VERSION 5.7 ;
  NOWIREEXTENSIONATPIN ON ;
  DIVIDERCHAR "/" ;
  BUSBITCHARS "[]" ;
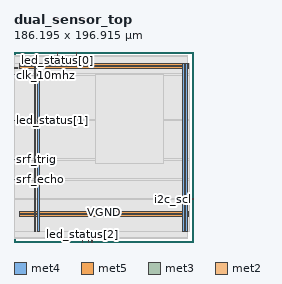
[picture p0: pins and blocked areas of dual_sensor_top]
MACRO dual_sensor_top
  CLASS BLOCK ;
  FOREIGN dual_sensor_top ;
  ORIGIN 0.000 0.000 ;
  SIZE 186.195 BY 196.915 ;
  PIN VGND
    DIRECTION INOUT ;
    USE GROUND ;
    PORT
      LAYER met4 ;
        RECT 24.340 10.640 25.940 185.200 ;
    END
    PORT
      LAYER met4 ;
        RECT 177.940 10.640 179.540 185.200 ;
    END
    PORT
      LAYER met5 ;
        RECT 5.280 30.030 180.560 31.630 ;
    END
    PORT
      LAYER met5 ;
        RECT 5.280 183.210 180.560 184.810 ;
    END
  END VGND
  PIN VPWR
    DIRECTION INOUT ;
    USE POWER ;
    PORT
      LAYER met4 ;
        RECT 21.040 10.640 22.640 185.200 ;
    END
    PORT
      LAYER met4 ;
        RECT 174.640 10.640 176.240 185.200 ;
    END
    PORT
      LAYER met5 ;
        RECT 5.280 26.730 180.560 28.330 ;
    END
    PORT
      LAYER met5 ;
        RECT 5.280 179.910 180.560 181.510 ;
    END
  END VPWR
  PIN clk_10mhz
    DIRECTION INPUT ;
    USE SIGNAL ;
    ANTENNAGATEAREA 0.852000 ;
    PORT
      LAYER met3 ;
        RECT 0.000 180.240 4.000 180.840 ;
    END
  END clk_10mhz
  PIN i2c_scl
    DIRECTION INOUT ;
    USE SIGNAL ;
    ANTENNADIFFAREA 1.782000 ;
    PORT
      LAYER met3 ;
        RECT 182.195 44.240 186.195 44.840 ;
    END
  END i2c_scl
  PIN i2c_sda
    DIRECTION INOUT ;
    USE SIGNAL ;
    ANTENNADIFFAREA 1.782000 ;
    PORT
      LAYER met2 ;
        RECT 80.590 0.000 80.870 4.000 ;
    END
  END i2c_sda
  PIN led_status[0]
    DIRECTION OUTPUT ;
    USE SIGNAL ;
    ANTENNADIFFAREA 0.445500 ;
    PORT
      LAYER met2 ;
        RECT 45.170 192.915 45.450 196.915 ;
    END
  END led_status[0]
  PIN led_status[1]
    DIRECTION OUTPUT ;
    USE SIGNAL ;
    ANTENNADIFFAREA 0.445500 ;
    PORT
      LAYER met3 ;
        RECT 0.000 125.840 4.000 126.440 ;
    END
  END led_status[1]
  PIN led_status[2]
    DIRECTION OUTPUT ;
    USE SIGNAL ;
    ANTENNADIFFAREA 0.445500 ;
    PORT
      LAYER met2 ;
        RECT 70.930 0.000 71.210 4.000 ;
    END
  END led_status[2]
  PIN pwr_ctrl
    DIRECTION OUTPUT ;
    USE SIGNAL ;
    ANTENNADIFFAREA 0.445500 ;
    PORT
      LAYER met2 ;
        RECT 77.370 0.000 77.650 4.000 ;
    END
  END pwr_ctrl
  PIN rst_n
    DIRECTION INPUT ;
    USE SIGNAL ;
    ANTENNAGATEAREA 0.196500 ;
    PORT
      LAYER met3 ;
        RECT 0.000 173.440 4.000 174.040 ;
    END
  END rst_n
  PIN srf_echo
    DIRECTION INPUT ;
    USE SIGNAL ;
    ANTENNAGATEAREA 0.196500 ;
    PORT
      LAYER met3 ;
        RECT 0.000 64.640 4.000 65.240 ;
    END
  END srf_echo
  PIN srf_trig
    DIRECTION OUTPUT ;
    USE SIGNAL ;
    ANTENNADIFFAREA 0.445500 ;
    PORT
      LAYER met3 ;
        RECT 0.000 85.040 4.000 85.640 ;
    END
  END srf_trig
  PIN uart_tx_pin
    DIRECTION OUTPUT ;
    USE SIGNAL ;
    ANTENNADIFFAREA 0.445500 ;
    PORT
      LAYER met2 ;
        RECT 64.490 192.915 64.770 196.915 ;
    END
  END uart_tx_pin
  OBS
      LAYER nwell ;
        RECT 5.330 10.795 180.510 185.045 ;
      LAYER li1 ;
        RECT 5.520 10.795 180.320 185.045 ;
      LAYER met1 ;
        RECT 4.210 10.640 180.320 185.200 ;
      LAYER met2 ;
        RECT 0.550 192.635 44.890 193.530 ;
        RECT 45.730 192.635 64.210 193.530 ;
        RECT 65.050 192.635 179.510 193.530 ;
        RECT 0.550 4.280 179.510 192.635 ;
        RECT 0.550 4.000 70.650 4.280 ;
        RECT 71.490 4.000 77.090 4.280 ;
        RECT 77.930 4.000 80.310 4.280 ;
        RECT 81.150 4.000 179.510 4.280 ;
      LAYER met3 ;
        RECT 0.525 181.240 182.195 185.125 ;
        RECT 4.400 179.840 182.195 181.240 ;
        RECT 0.525 174.440 182.195 179.840 ;
        RECT 4.400 173.040 182.195 174.440 ;
        RECT 0.525 126.840 182.195 173.040 ;
        RECT 4.400 125.440 182.195 126.840 ;
        RECT 0.525 86.040 182.195 125.440 ;
        RECT 4.400 84.640 182.195 86.040 ;
        RECT 0.525 65.640 182.195 84.640 ;
        RECT 4.400 64.240 182.195 65.640 ;
        RECT 0.525 45.240 182.195 64.240 ;
        RECT 0.525 43.840 181.795 45.240 ;
        RECT 0.525 10.715 182.195 43.840 ;
      LAYER met4 ;
        RECT 84.935 81.095 155.185 173.225 ;
  END
END dual_sensor_top
END LIBRARY

